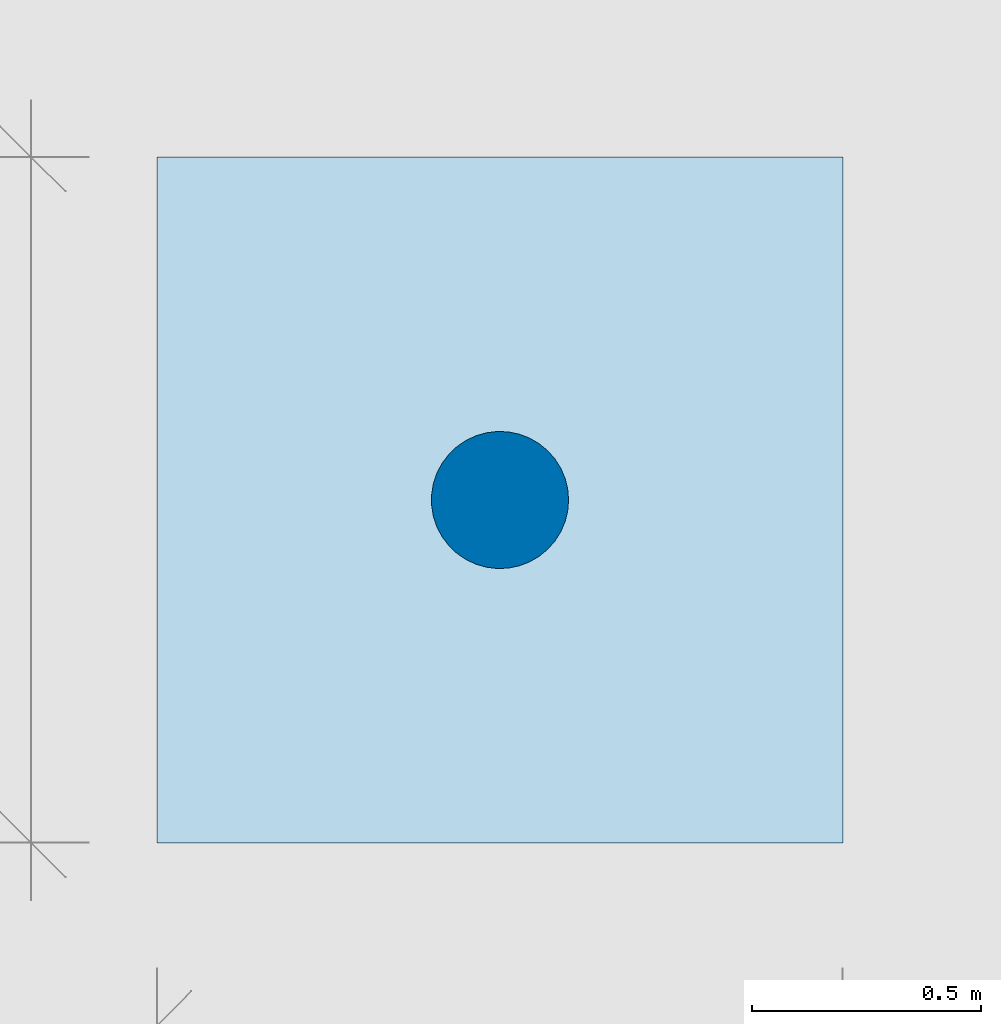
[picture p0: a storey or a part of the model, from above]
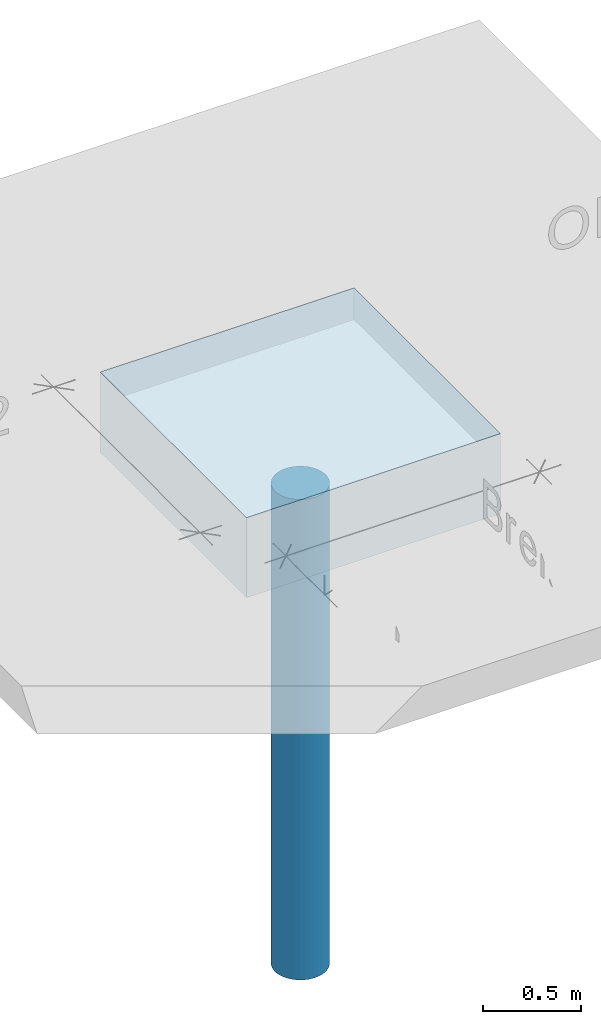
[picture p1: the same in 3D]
Properties of the parts of a building model (IFC4)

# File
Description: no view
File name: ÖBV_OEBV_Richtlinie_Deckenpilz.ifc
Time: 2024-03-13T09:56:09
Author: Oesterreichische Bautechnik Vereinigung
Organization: OEBV
Written by: ODA SDAI 24.5
Authorization: OEBV

# IfcSite, Liegenschaft
RefLatitude: 48, 8, 10, 320000; RefLongitude: 11, 41, 19, 320000

# IfcBuildingStorey, Geschoss 01
In: Gebäude
Elevation: 0 m

# IfcBuildingElementProxy (9)
In: Geschoss 01
Name | Allright_Bauteil_ID
macro | 0032Mak0000000038
macro | 0032Mak0000000077
macro | 0032Mak0000000016
macro | 0032Mak0000000052
macro | 0032Mak0000000027
macro | 0032Mak0000000066
macro | 0032Mak0000000086
macro | 0032Mak0000000095
 | 0032ErE0000000002

# IfcColumn
In: Geschoss 01
PredefinedType: COLUMN; Material: C25/30
AllplanAttributes - Allright_Bauteil_ID: 0032St 0000000097

# IfcElementAssembly (8)
In: Geschoss 01
Name | Allright_Bauteil_ID
SpatialDim_Group | 0032Elg0000000039
SpatialDim_Group | 0032Elg0000000078
SpatialDim_Group | 0032Elg0000000017
SpatialDim_Group | 0032Elg0000000053
SpatialDim_Group | 0032Elg0000000028
SpatialDim_Group | 0032Elg0000000067
SpatialDim_Group | 0032Elg0000000087
SpatialDim_Group | 0032Elg0000000096

# IfcSlab
In: Geschoss 01
PredefinedType: FLOOR; Material: Gelände
AllplanAttributes - Allright_Bauteil_ID: 0032De 0000004385
